VERSION 5.7 ;
DIVIDERCHAR "/" ;
BUSBITCHARS "[]" ;

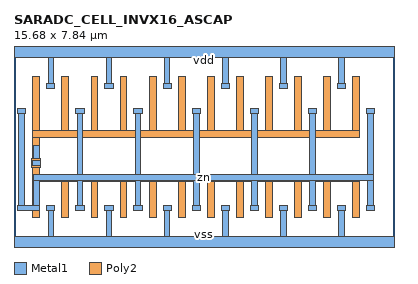
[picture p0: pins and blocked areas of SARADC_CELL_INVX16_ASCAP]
MACRO SARADC_CELL_INVX16_ASCAP
  CLASS BLOCK ;
  FOREIGN SARADC_CELL_INVX16_ASCAP ;
  ORIGIN 0.000 0.000 ;
  SIZE 15.680 BY 7.840 ;
  SYMMETRY X Y R90 ;
  PIN vnw
  END vnw
  PIN vpw
  END vpw
  PIN vdd
    DIRECTION INOUT ;
    USE POWER ;
    PORT
      LAYER Metal1 ;
        RECT 1.350 6.330 1.690 6.560 ;
        RECT 3.750 6.330 4.090 6.560 ;
        RECT 6.150 6.330 6.490 6.560 ;
        RECT 8.550 6.330 8.890 6.560 ;
        RECT 10.950 6.330 11.290 6.560 ;
        RECT 13.350 6.330 13.690 6.560 ;
        RECT 1.405 6.560 1.635 7.610 ;
        RECT 3.805 6.560 4.035 7.610 ;
        RECT 6.205 6.560 6.435 7.610 ;
        RECT 8.605 6.560 8.835 7.610 ;
        RECT 11.005 6.560 11.235 7.610 ;
        RECT 13.405 6.560 13.635 7.610 ;
        RECT 0.000 7.610 15.680 8.070 ;
    END
  END vdd
  PIN vss
    DIRECTION INOUT ;
    USE GROUND ;
    PORT
      LAYER Metal1 ;
        RECT 0.000 -0.230 15.680 0.230 ;
        RECT 1.405 0.230 1.635 1.280 ;
        RECT 3.805 0.230 4.035 1.280 ;
        RECT 6.205 0.230 6.435 1.280 ;
        RECT 8.605 0.230 8.835 1.280 ;
        RECT 11.005 0.230 11.235 1.280 ;
        RECT 13.405 0.230 13.635 1.280 ;
        RECT 1.350 1.280 1.690 1.510 ;
        RECT 3.750 1.280 4.090 1.510 ;
        RECT 6.150 1.280 6.490 1.510 ;
        RECT 8.550 1.280 8.890 1.510 ;
        RECT 10.950 1.280 11.290 1.510 ;
        RECT 13.350 1.280 13.690 1.510 ;
    END
  END vss
  PIN i
    DIRECTION INOUT ;
    USE POWER ;
    PORT
      LAYER Poly2 ;
        RECT 0.780 0.995 1.060 2.515 ;
        RECT 1.980 0.995 2.260 2.515 ;
        RECT 3.180 0.995 3.460 2.515 ;
        RECT 4.380 0.995 4.660 2.515 ;
        RECT 5.580 0.995 5.860 2.515 ;
        RECT 6.780 0.995 7.060 2.515 ;
        RECT 7.980 0.995 8.260 2.515 ;
        RECT 9.180 0.995 9.460 2.515 ;
        RECT 10.380 0.995 10.660 2.515 ;
        RECT 11.580 0.995 11.860 2.515 ;
        RECT 12.780 0.995 13.060 2.515 ;
        RECT 13.980 0.995 14.260 2.515 ;
        RECT 0.780 2.515 14.260 2.795 ;
        RECT 0.780 2.795 1.060 3.075 ;
        RECT 0.740 3.075 1.100 3.435 ;
        RECT 0.780 3.435 1.060 4.315 ;
        RECT 0.780 4.315 14.260 4.595 ;
        RECT 0.780 4.595 1.060 6.845 ;
        RECT 1.980 4.595 2.260 6.845 ;
        RECT 3.180 4.595 3.460 6.845 ;
        RECT 4.380 4.595 4.660 6.845 ;
        RECT 5.580 4.595 5.860 6.845 ;
        RECT 6.780 4.595 7.060 6.845 ;
        RECT 7.980 4.595 8.260 6.845 ;
        RECT 9.180 4.595 9.460 6.845 ;
        RECT 10.380 4.595 10.660 6.845 ;
        RECT 11.580 4.595 11.860 6.845 ;
        RECT 12.780 4.595 13.060 6.845 ;
        RECT 13.980 4.595 14.260 6.845 ;
      LAYER Metal1 ;
        RECT 0.750 3.140 1.090 3.370 ;
        RECT 0.805 3.370 1.035 3.970 ;
    END
  END i
  PIN zn
    DIRECTION INOUT ;
    USE POWER ;
    PORT
      LAYER Metal1 ;
        RECT 0.150 1.280 1.035 1.510 ;
        RECT 2.550 1.280 2.890 1.510 ;
        RECT 4.950 1.280 5.290 1.510 ;
        RECT 7.350 1.280 7.690 1.510 ;
        RECT 9.750 1.280 10.090 1.510 ;
        RECT 12.150 1.280 12.490 1.510 ;
        RECT 14.550 1.280 14.890 1.510 ;
        RECT 0.205 1.510 0.435 5.290 ;
        RECT 0.805 1.510 1.035 2.540 ;
        RECT 2.605 1.510 2.835 2.540 ;
        RECT 5.005 1.510 5.235 2.540 ;
        RECT 7.405 1.510 7.635 2.540 ;
        RECT 9.805 1.510 10.035 2.540 ;
        RECT 12.205 1.510 12.435 2.540 ;
        RECT 14.605 1.510 14.835 2.540 ;
        RECT 0.805 2.540 14.835 2.770 ;
        RECT 2.605 2.770 2.835 5.290 ;
        RECT 5.005 2.770 5.235 5.290 ;
        RECT 7.405 2.770 7.635 5.290 ;
        RECT 9.805 2.770 10.035 5.290 ;
        RECT 12.205 2.770 12.435 5.290 ;
        RECT 14.605 2.770 14.835 5.290 ;
        RECT 0.150 5.290 0.490 5.520 ;
        RECT 2.550 5.290 2.890 5.520 ;
        RECT 4.950 5.290 5.290 5.520 ;
        RECT 7.350 5.290 7.690 5.520 ;
        RECT 9.750 5.290 10.090 5.520 ;
        RECT 12.150 5.290 12.490 5.520 ;
        RECT 14.550 5.290 14.890 5.520 ;
    END
  END zn
END SARADC_CELL_INVX16_ASCAP

END LIBRARY
